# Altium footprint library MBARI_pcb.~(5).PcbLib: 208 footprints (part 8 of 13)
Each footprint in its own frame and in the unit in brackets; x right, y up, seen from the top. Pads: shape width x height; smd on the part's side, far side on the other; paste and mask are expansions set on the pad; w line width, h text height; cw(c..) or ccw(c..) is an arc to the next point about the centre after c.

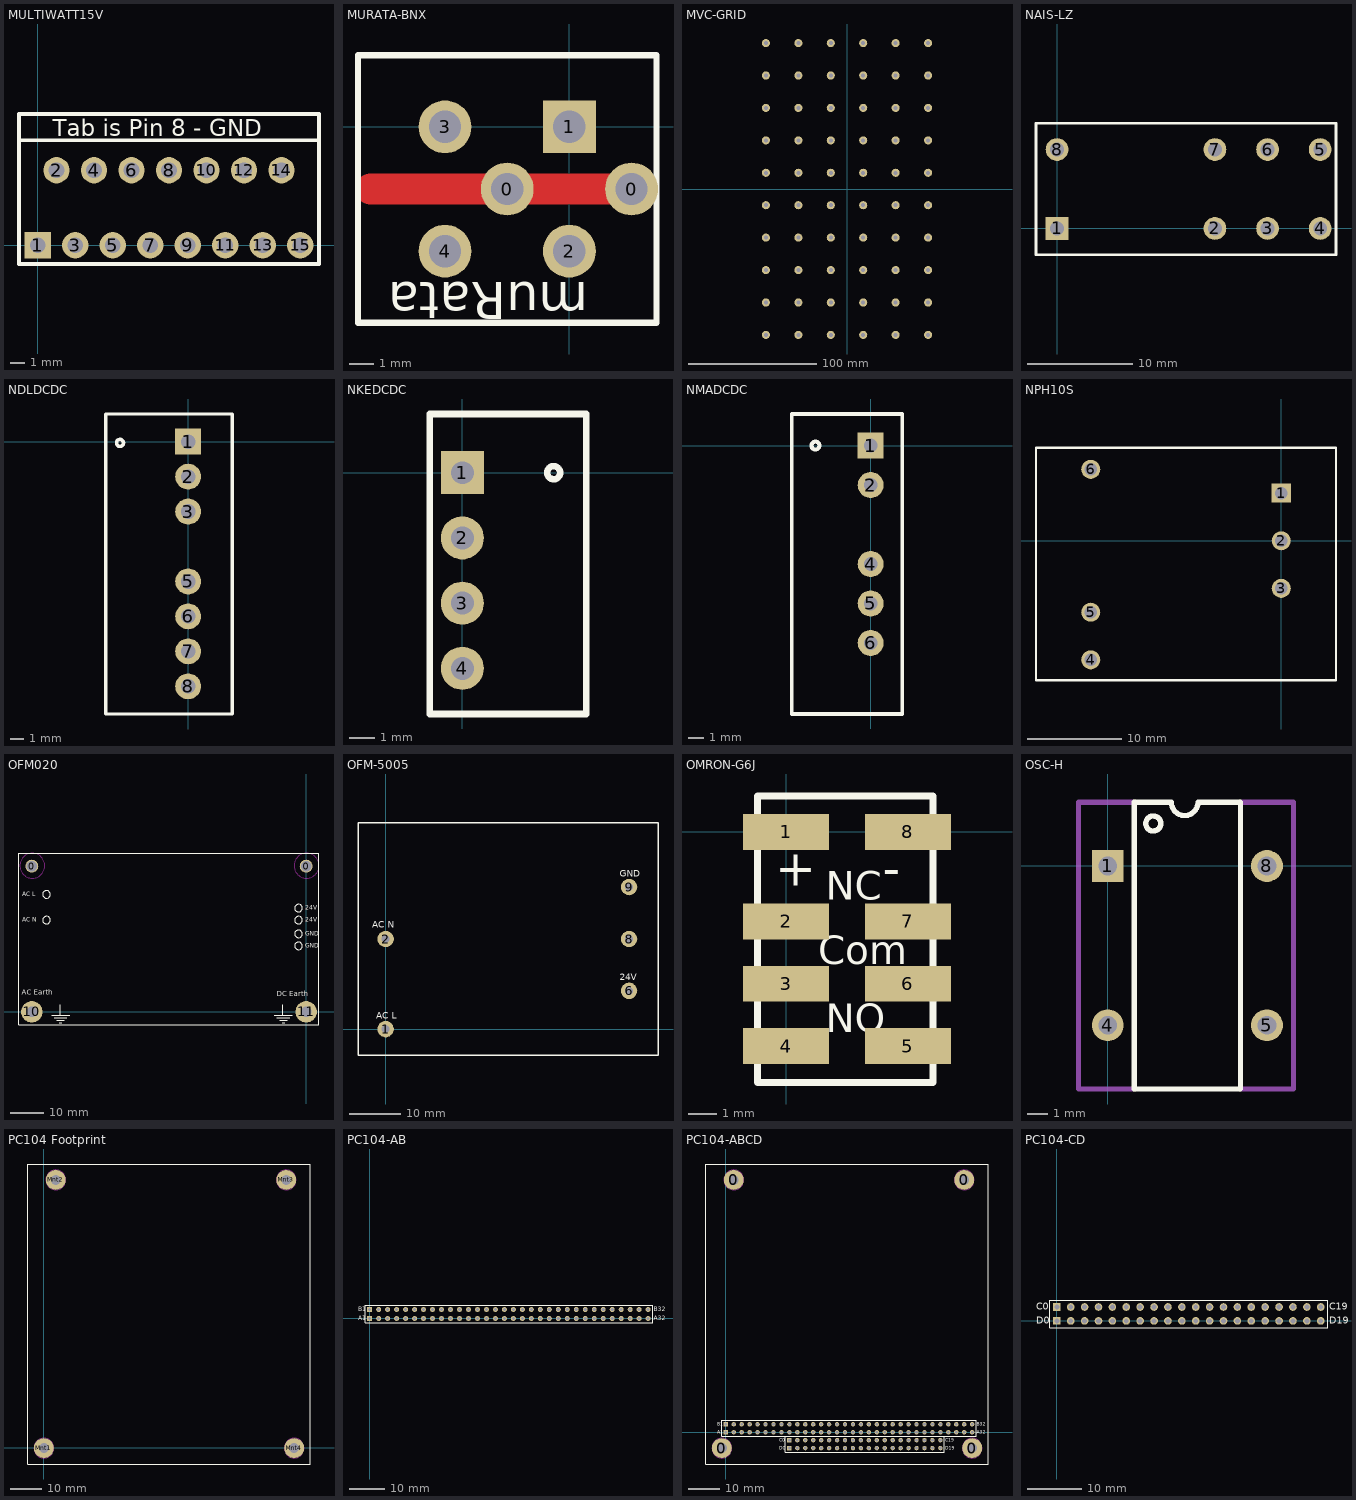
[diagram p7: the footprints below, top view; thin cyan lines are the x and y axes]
## MULTIWATT15V [mil]
pads (15):
  rect 70x70 hole 42: 1(0,0)
  round 70 hole 42: 2(50,200) 3(100,0) 4(150,200) 5(200,0) 6(250,200) 7(300,0) 8(350,200) 9(400,0) 10(450,200) 11(500,0) 12(550,200) 13(600,0) 14(650,200) 15(700,0)
TopOverlay:
  lines w10: -50,280 750,280 ; -50,-50 750,-50 750,350 -50,350 -50,-50
  text "Tab is Pin 8 - GND" at 40,290 h45

## MURATA-BNX [mil]
pads (6):
  round 85 hole 52: 0(-100,-100) 0(100,-100) 2(0,-200) 3(-200,0) 4(-200,-200)
  rect 85x85 hole 52: 1(0,0)
TopLayer:
  lines w50: -320,-100 100,-100
TopOverlay:
  lines w10: -340,-315 -340,115 140,115 140,-315 -340,-315
  text "muRata" at 30,-250 h60

## MVC-GRID [mil]
pads (60):
  round 250 hole 125: 00(-2500,4500) 01(-2500,3500) 02(-2500,2500) 03(-2500,1500) 04(-2500,500) 05(-2500,-500) 06(-2500,-1500) 07(-2500,-2500) 08(-2500,-3500) 09(-2500,-4500) 10(-1500,4500) 11(-1500,3500) 12(-1500,2500) 13(-1500,1500) 14(-1500,500) 15(-1500,-500) 16(-1500,-1500) 17(-1500,-2500) 18(-1500,-3500) 19(-1500,-4500) 20(-500,4500) 21(-500,3500) 22(-500,2500) 23(-500,1500) 24(-500,500) 25(-500,-500) 26(-500,-1500) 27(-500,-2500) 28(-500,-3500) 29(-500,-4500) 30(500,4500) 31(500,3500) 32(500,2500) 33(500,1500) 34(500,500) 35(500,-500) 36(500,-1500) 37(500,-2500) 38(500,-3500) 39(500,-4500) 40(1500,4500) 41(1500,3500) 42(1500,2500) 43(1500,1500) 44(1500,500) 45(1500,-500) 46(1500,-1500) 47(1500,-2500) 48(1500,-3500) 49(1500,-4500) 50(2500,4500) 51(2500,3500) 52(2500,2500) 53(2500,1500) 54(2500,500) 55(2500,-500) 56(2500,-1500) 57(2500,-2500) 58(2500,-3500) 59(2500,-4500)

## NAIS-LZ [mil] "NAIS LZ Relay"
height 24330.71
pads (8):
  rect 85x85 hole 52: 1(0,0)
  round 85 hole 52: 2(590.55,0) 3(787.4,0) 4(984.25,0) 5(984.25,295.28) 6(787.4,295.28) 7(590.55,295.28) 8(0,295.28)
TopOverlay:
  lines w10: -78.74,-98.43 -78.74,393.7 1043.31,393.7 1043.31,-98.43 -78.74,-98.43

## NDLDCDC [mil]
pads (7):
  rect 74x74 hole 42: 1(0,0)
  round 74 hole 42: 2(0,-100) 3(0,-200) 5(0,-400) 6(0,-500) 7(0,-600) 8(0,-700)
TopOverlay:
  circle w10: c-195.04,-3.54 r10
  lines w10: -236.22,-779.29 -236.22,79.13 -36.22,79.13 126.46,79.13 126.46,-779.29 -236.22,-779.29

## NKEDCDC [mil]
pads (4):
  rect 66x66 hole 35: 1(0,0)
  round 66 hole 35: 2(0,-100) 3(0,-200) 4(0,-300)
TopOverlay:
  circle w10: c140,0 r10
  lines w10: -50,-370 190,-370 190,90 -50,90 -50,-370

## NMADCDC [mil]
pads (5):
  rect 66x66 hole 35: 1(0,0)
  round 66 hole 35: 2(0,-100) 4(0,-300) 5(0,-400) 6(0,-500)
TopOverlay:
  circle w10: c-140,0 r10
  lines w10: -200,-680 -200,80 0,80 80,80 80,-680 -200,-680

## NPH10S [mil] "C&D NPH10S series isol DC->DC converter"
height 390
pads (6):
  rect 80x80 hole 52: 1(0,200)
  round 80 hole 52: 2(0,0) 3(0,-200) 4(-800,-500) 5(-800,-300) 6(-800,300)
TopOverlay:
  lines w10: -1030,-585 -1030,390 230,390 230,-585 -1030,-585

## OFM020 [mil]
pads (4):
  round 150 hole 125: 0(-3200,1700) 0(0,1700)
  round 250 hole 125: 10(-3200,0) 11(0,0)
TopOverlay:
  circle w10: c-90,770 r44.72
  circle w10: c-90,1070 r44.72
  circle w10: c-90,910 r44.72
  circle w10: c-90,1210 r44.72
  circle w10: c-3030,1070 r44.72
  circle w10: c-3030,1370 r44.72
  lines w10: -2970,-40 -2760,-40 ; -2940,-70 -2790,-70 ; -2910,-100 -2820,-100 ; -2880,-130 -2850,-130 ; -2870,-40 -2870,80 ; -370,-40 -160,-40 ; -340,-70 -190,-70 ; -310,-100 -220,-100 ; -280,-130 -250,-130 ; -270,-40 -270,80 ; -3350,-150 150,-150 150,1850 -3350,1850 -3350,-150
  text "GND" at -10,750 h50
  text "24V" at -10,1050 h50
  text "24V" at -10,1190 h50
  text "AC N" at -3310,1050 h50
  text "AC L" at -3310,1350 h50
  text "GND" at -10,890 h50
  text "AC Earth" at -3320,200 h60
  text "DC Earth" at -340,180 h60
KeepOutLayer:
  circle w10: c-3195,1705 r145
  circle w10: c5,1705 r145

## OFM-5005 [mil]
pads (5):
  round 125 hole 59.5: 1(0,0) 2(0,685) 6(1850,291) 8(1850,685) 9(1850,1080)
TopOverlay:
  lines w10: -210,-200 -210,0 -210,1570 2070,1570 2070,-200 -210,-200
  text "AC L" at -70,80 h50
  text "24V" at 1780,370 h50
  text "AC N" at -100,770 h50
  text "GND" at 1780,1160 h50

## OMRON-G6J [mil]
pads (8):
  rect 120x50 smd: 1(0,0) 2(0,-125) 3(0,-212) 4(0,-299) 5(170,-299) 6(170,-212) 7(170,-125) 8(170,0)
TopOverlay:
  lines w10: -40,-350 -40,50 205,50 205,-350 -40,-350
  text "Com" at 45,-185 h40
  text "NO" at 55,-280 h40
  text "NC" at 55,-95 h40
  text "-" at 135,-75 h50
  text "+" at -15,-75 h50

## OSC-H [mil]
pads (4):
  rect 60x60 hole 35: 1(0,0)
  round 60 hole 35: 4(0,-300) 5(300,-300) 8(300,0)
TopOverlay:
  circle w10: c85.86,80 r14.14
  lines w10: 50,-420 50,120 120,120 ccw(c145,120) 170,120 250,120 250,-420 50,-420
Mechanical1:
  lines w10: 50,-420 -55,-420 -55,120 51,120 ; 250,-420 350,-420 350,120 250,120

## PC104 Footprint [mil] "PC104 Footprint"
pads (4):
  round 250 hole 125: Mnt1(0,-5) Mnt2(150,3370) Mnt3(3050,3370) Mnt4(3150,-5)
TopOverlay:
  lines w10: -200,-205 -200,3570 3350,3570 3350,-205 -200,-205
KeepOutLayer:
  circle w10: c0,-5 r125
  circle w10: c150,3370 r125
  circle w10: c3050,3370 r125
  circle w10: c3150,-5 r125

## PC104-AB [mil] "PC/104 A&B rails"
height 440
pads (64):
  rect 55x55 hole 35: A1(0,0) B1(0,100)
  round 55 hole 35: A2(100,0) A3(200,0) A4(300,0) A5(400,0) A6(500,0) A7(600,0) A8(700,0) A9(800,0) A10(900,0) A11(1000,0) A12(1100,0) A13(1200,0) A14(1300,0) A15(1400,0) A16(1500,0) A17(1600,0) A18(1700,0) A19(1800,0) A20(1900,0) A21(2000,0) A22(2100,0) A23(2200,0) A24(2300,0) A25(2400,0) A26(2500,0) A27(2600,0) A28(2700,0) A29(2800,0) A30(2900,0) A31(3000,0) A32(3100,0) B2(100,100) B3(200,100) B4(300,100) B5(400,100) B6(500,100) B7(600,100) B8(700,100) B9(800,100) B10(900,100) B11(1000,100) B12(1100,100) B13(1200,100) B14(1300,100) B15(1400,100) B16(1500,100) B17(1600,100) B18(1700,100) B19(1800,100) B20(1900,100) B21(2000,100) B22(2100,100) B23(2200,100) B24(2300,100) B25(2400,100) B26(2500,100) B27(2600,100) B28(2700,100) B29(2800,100) B30(2900,100) B31(3000,100) B32(3100,100)
TopOverlay:
  lines w8: 3150,-50.39 3150,149.61 ; 3150,-50 -50,-50.39 -50,149.61 3150,150
  text "B32" at 3160,79.61 h50
  text "A32" at 3160,-20.39 h50
  text "A1" at -130,-20 h50
  text "B1" at -130,80 h50

## PC104-ABCD [mil] "PC104 Outline and ABCD Rails"
height 600
pads (108):
  round 250 hole 125: 0(-50,-200) 0(100,3175) 0(3000,3175) 0(3100,-200)
  rect 55x55 hole 35: A1(0,0) B1(0,100) C0(800,-100) D0(800,-200)
  round 55 hole 35: A2(100,0) A3(200,0) A4(300,0) A5(400,0) A6(500,0) A7(600,0) A8(700,0) A9(800,0) A10(900,0) A11(1000,0) A12(1100,0) A13(1200,0) A14(1300,0) A15(1400,0) A16(1500,0) A17(1600,0) A18(1700,0) A19(1800,0) A20(1900,0) A21(2000,0) A22(2100,0) A23(2200,0) A24(2300,0) A25(2400,0) A26(2500,0) A27(2600,0) A28(2700,0) A29(2800,0) A30(2900,0) A31(3000,0) A32(3100,0) B2(100,100) B3(200,100) B4(300,100) B5(400,100) B6(500,100) B7(600,100) B8(700,100) B9(800,100) B10(900,100) B11(1000,100) B12(1100,100) B13(1200,100) B14(1300,100) B15(1400,100) B16(1500,100) B17(1600,100) B18(1700,100) B19(1800,100) B20(1900,100) B21(2000,100) B22(2100,100) B23(2200,100) B24(2300,100) B25(2400,100) B26(2500,100) B27(2600,100) B28(2700,100) B29(2800,100) B30(2900,100) B31(3000,100) B32(3100,100) C1(900,-100) C2(1000,-100) C3(1100,-100) C4(1200,-100) C5(1300,-100) C6(1400,-100) C7(1500,-100) C8(1600,-100) C9(1700,-100) C10(1800,-100) C11(1900,-100) C12(2000,-100) C13(2100,-100) C14(2200,-100) C15(2300,-100) C16(2400,-100) C17(2500,-100) C18(2600,-100) C19(2700,-100) D1(900,-200) D2(1000,-200) D3(1100,-200) D4(1200,-200) D5(1300,-200) D6(1400,-200) D7(1500,-200) D8(1600,-200) D9(1700,-200) D10(1800,-200) D11(1900,-200) D12(2000,-200) D13(2100,-200) D14(2200,-200) D15(2300,-200) D16(2400,-200) D17(2500,-200) D18(2600,-200) D19(2700,-200)
TopOverlay:
  lines w8: 3150,-50.39 3150,149.61 ; 3150,-50 -50,-50.39 -50,149.61 3150,150 ; 750,-250.39 750,-50.39 2750,-50 2750,-250 750,-250.39
  lines w10: -250,-400 -250,3375 3300,3375 3300,-400 -250,-400
  text "C0" at 670,-120 h40
  text "D0" at 670,-220 h40
  text "D19" at 2760,-220.39 h40
  text "C19" at 2760,-120.39 h40
  text "B32" at 3160,79.61 h40
  text "A32" at 3160,-20.39 h40
  text "A1" at -110,-20 h40
  text "B1" at -110,80 h40
KeepOutLayer:
  circle w10: c-50,-200 r125
  circle w10: c100,3175 r125
  circle w10: c3000,3175 r125
  circle w10: c3100,-200 r125

## PC104-CD [mil] "PC/104 C&D rails"
height 440
pads (40):
  rect 55x55 hole 35: C0(0,100) D0(0,0)
  round 55 hole 35: C1(100,100) C2(200,100) C3(300,100) C4(400,100) C5(500,100) C6(600,100) C7(700,100) C8(800,100) C9(900,100) C10(1000,100) C11(1100,100) C12(1200,100) C13(1300,100) C14(1400,100) C15(1500,100) C16(1600,100) C17(1700,100) C18(1800,100) C19(1900,100) D1(100,0) D2(200,0) D3(300,0) D4(400,0) D5(500,0) D6(600,0) D7(700,0) D8(800,0) D9(900,0) D10(1000,0) D11(1100,0) D12(1200,0) D13(1300,0) D14(1400,0) D15(1500,0) D16(1600,0) D17(1700,0) D18(1800,0) D19(1900,0)
TopOverlay:
  lines w8: -50,-50.39 1950,-50 1950,150 -50,149.61 -50,-50.39
  text "C19" at 1960,79.61 h50
  text "D19" at 1960,-20.39 h50
  text "D0" at -150,-20 h50
  text "C0" at -150,80 h50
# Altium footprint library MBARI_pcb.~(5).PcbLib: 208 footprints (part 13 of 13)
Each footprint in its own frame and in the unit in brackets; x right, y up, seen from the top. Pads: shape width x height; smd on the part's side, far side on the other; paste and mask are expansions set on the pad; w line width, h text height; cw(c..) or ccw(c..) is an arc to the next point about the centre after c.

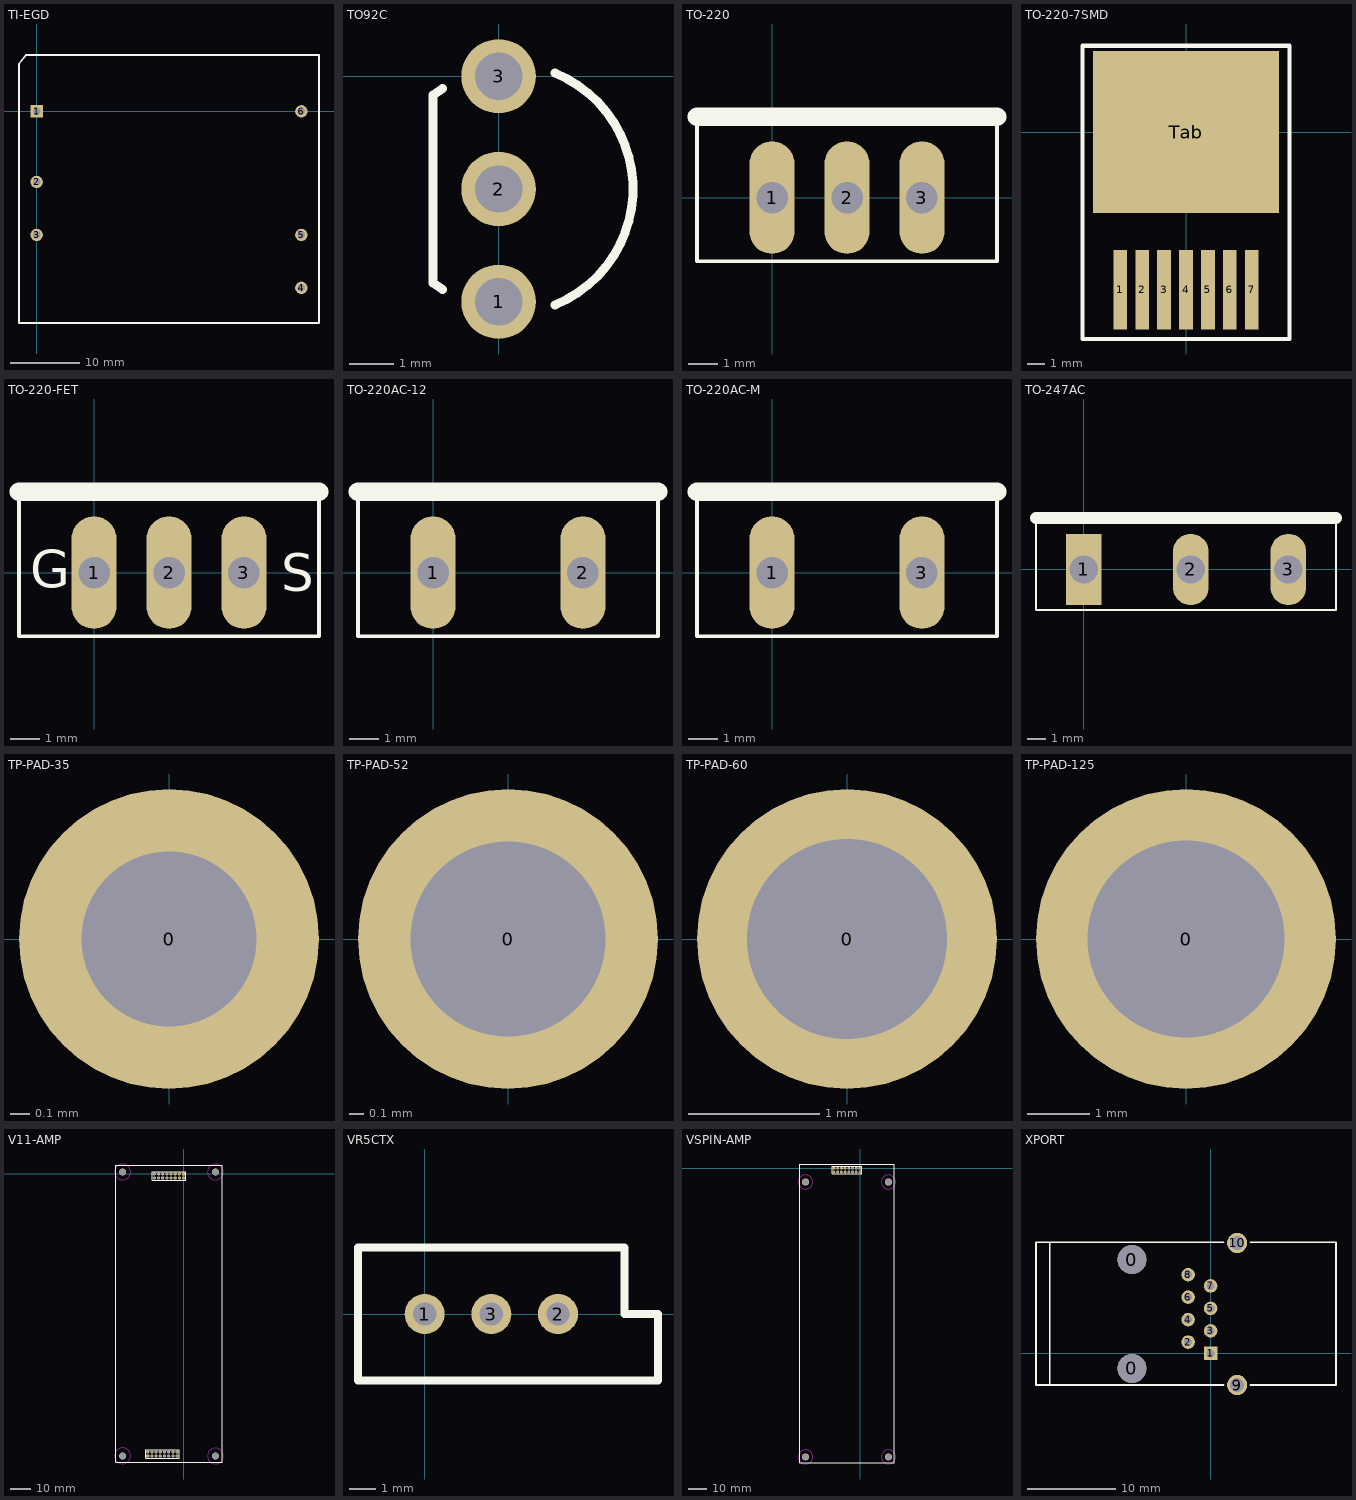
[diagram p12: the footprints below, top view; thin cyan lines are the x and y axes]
## TI-EGD [mil] "TI Powertrends EGD package for isol DC->DC converters"
height 330
pads (6):
  rect 70x70 hole 42: 1(0,0)
  round 70 hole 42: 2(0,-400) 3(0,-700) 4(1500,-1000) 5(1500,-700) 6(1500,0)
TopOverlay:
  lines w10: -100,-1200 -100,270 -60,320 1600,320 1600,-1200 -100,-1200

## TO92C [mil]
pads (3):
  round 66 hole 42: 1(0,-200) 2(0,-100) 3(0,0)
TopOverlay:
  lines w7.87: -49.71,-189.08 -58.33,-183.33 -58.33,-16.67 -49.71,-10.92 ; 49.85,-202.76 ccw(c8.33,-100) 49.85,2.76

## TO-220 [mil]
pads (3):
  oval 60x150 hole 42: 1(0,0) 2(100,0) 3(200,0)
TopOverlay:
  lines w5: -100,108 -100,-85 300,-85 300,108
  lines w25: -100,108 300,108

## TO-220-7SMD [mm] "TO-220 Surface Mount 7 leads"
height 4.4
pads (8):
  rect 0.8x4.6 smd: 1(-3.81,-9.14) 2(-2.54,-9.14) 3(-1.27,-9.14) 4(0,-9.14) 5(1.27,-9.14) 6(2.54,-9.14) 7(3.81,-9.14)
  rect 10.8x9.4 smd: Tab(0,0)
TopOverlay:
  lines w0.254: -6,-12 6,-12 6,5 -6,5 -6,-12

## TO-220-FET [mil]
pads (3):
  oval 60x150 hole 42: 1(0,0) 2(100,0) 3(200,0)
TopOverlay:
  lines w5: -100,108 -100,-85 300,-85 300,108
  lines w25: -100,108 300,108
  text "G" at -85,-20 h50
  text "S" at 250,-25 h50

## TO-220AC-12 [mil]
pads (2):
  oval 60x150 hole 42: 1(0,0) 2(200,0)
TopOverlay:
  lines w5: -100,108 -100,-85 300,-85 300,108
  lines w25: -100,108 300,108

## TO-220AC-M [mil]
pads (2):
  oval 60x150 hole 42: 1(0,0) 3(200,0)
TopOverlay:
  lines w5: -100,108 -100,-85 300,-85 300,108
  lines w25: -100,108 300,108

## TO-247AC [mil]
height 970
pads (3):
  rect 75x150 hole 59.5: 1(0,0)
  oval 75x150 hole 59.5: 2(225,0) 3(430,0)
TopOverlay:
  lines w5: -100,108 -100,-85 530,-85 530,108
  lines w25: -100,108 530,108

## TP-PAD-35 [mil] "TestPoint 35mil"
pads (1):
  round 60 hole 35: 0(0,0)

## TP-PAD-52 [mil]
pads (1):
  round 80 hole 52: 0(0,0)

## TP-PAD-60 [mil]
pads (1):
  round 90 hole 60: 0(0,0)

## TP-PAD-125 [mil]
pads (1):
  round 190 hole 125: 0(0,0)

## V11-AMP [mil]
pads (36):
  round 130 hole 125: 0(-1150,-5320) 0(-1150,35) 0(600,-5320) 0(600,35)
  rect 60x60 hole 35: M1(-675,-5320) S1(0,0)
  round 60 hole 35: M2(-675,-5241.26) M3(-596.26,-5320) M4(-596.26,-5241.26) M5(-517.52,-5320) M6(-517.52,-5241.26) M7(-438.78,-5320) M8(-438.78,-5241.26) M9(-360.04,-5320) M10(-360.04,-5241.26) M11(-281.3,-5320) M12(-281.3,-5241.26) M13(-202.56,-5320) M14(-202.56,-5241.26) M15(-123.82,-5320) M16(-123.82,-5241.26) S2(0,-78.74) S3(-78.74,0) S4(-78.74,-78.74) S5(-157.48,0) S6(-157.48,-78.74) S7(-236.22,0) S8(-236.22,-78.74) S9(-314.96,0) S10(-314.96,-78.74) S11(-393.7,0) S12(-393.7,-78.74) S13(-472.44,0) S14(-472.44,-78.74) S15(-551.18,0) S16(-551.18,-78.74)
TopOverlay:
  lines w8: -715,-5360 -715,-5200 -85,-5200 -85,-5360 -715,-5360 ; -590,-120 -590,40 40,40 40,-120 -590,-120
  lines w10: -1275,-5440 -1275,160 725,160 725,-5440 -1275,-5440
BottomOverlay:
  text "Sense/Logic" at -120,-160 h45
  text "Phases" at -300,-5200 h45
KeepOutLayer:
  circle w10: c-1150,35 r150
  circle w10: c600,35 r150
  circle w10: c600,-5320 r150
  circle w10: c-1150,-5315 r150

## VR5CTX [mil]
pads (3):
  round 60 hole 35: 1(0,0) 2(200,0) 3(100,0)
TopOverlay:
  lines w12: -100,-100 350,-100 350,0 300,0 300,100 -100,100 -100,-100

## VSPIN-AMP [mil]
pads (20):
  round 150 hole 125: 0(-1150,-6090) 0(-1150,-290) 0(600,-6090) 0(600,-290)
  rect 60x60 hole 35: 1(0,0)
  round 60 hole 35: 2(0,-78.74) 3(-78.74,0) 4(-78.74,-78.74) 5(-157.48,0) 6(-157.48,-78.74) 7(-236.22,0) 8(-236.22,-78.74) 9(-314.96,0) 10(-314.96,-78.74) 11(-393.7,0) 12(-393.7,-78.74) 13(-472.44,0) 14(-472.44,-78.74) 15(-551.18,0) 16(-551.18,-78.74)
TopOverlay:
  lines w8: -590,-120 40,-120 40,40 -590,40 -590,-120
  lines w10: -1275,-6210 725,-6210 725,90 -1275,90 -1275,-6210
BottomOverlay:
  text "Amp Logic" at -140,-170 h45
KeepOutLayer:
  circle w10: c-1150,-290 r150
  circle w10: c600,-290 r150
  circle w10: c-1150,-6090 r150
  circle w10: c600,-6090 r150

## XPORT [mil]
pads (12):
  round 128 hole 128 unplated: 0(-350,-67) 0(-350,417)
  rect 60x60 hole 35: 1(0,0)
  round 60 hole 35: 2(-100,50) 3(0,100) 4(-100,150) 5(0,200) 6(-100,250) 7(0,300) 8(-100,350)
  round 90 hole 63: 9(118,-141) 10(118,491)
TopOverlay:
  lines w7: -715,-141 -715,494
  lines w8: 58,-141 -777,-141 -777,-121 -777,494 58,494 ; 178,-141 558,-141 558,494 178,494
